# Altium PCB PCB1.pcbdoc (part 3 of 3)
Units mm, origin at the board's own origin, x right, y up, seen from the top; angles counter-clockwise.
Board outline 85.01 x 107.37 mm, 4 copper layers (Top Layer, Inner1, Inner2, Bottom Layer); 103 components, 144 nets, 660 pads, 278 vias.

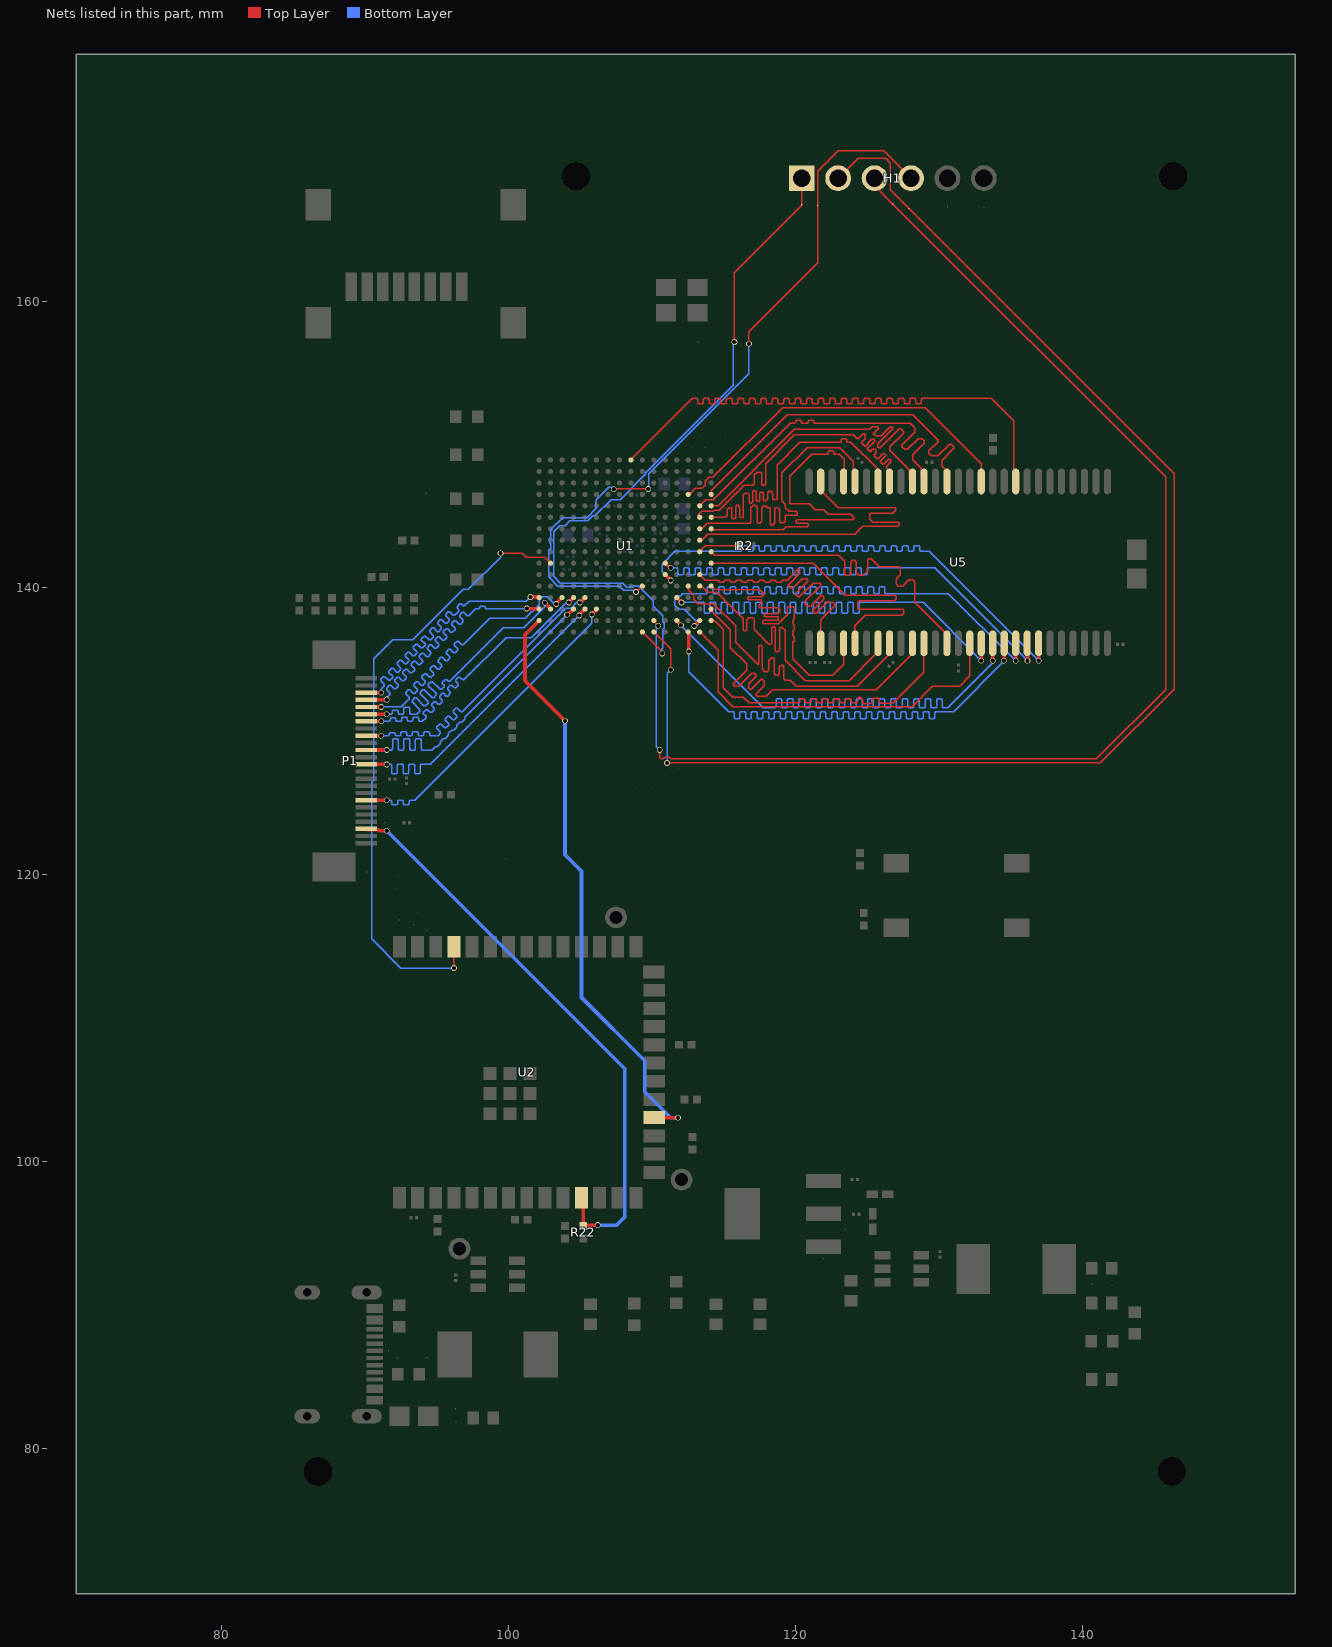
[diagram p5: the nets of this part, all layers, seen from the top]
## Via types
v1: diameter 0.4, hole 0.3, Top Layer to Bottom Layer, 262 vias
v2: diameter 0.61, hole 0.305, Top Layer to Bottom Layer, 16 vias

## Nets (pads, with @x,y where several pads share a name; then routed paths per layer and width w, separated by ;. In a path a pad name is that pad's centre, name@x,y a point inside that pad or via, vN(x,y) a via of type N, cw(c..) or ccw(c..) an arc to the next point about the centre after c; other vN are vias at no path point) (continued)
SD_A12: U1.A9 U5.36 | length 45.3
  Top Layer w0.1: U1.A9@108.528,148.926 112.815,153.213 113.115,153.213 113.186,153.142 113.186,152.903 113.256,152.832 113.515,152.832 113.586,152.903 113.586,153.142 113.656,153.213 113.915,153.213 113.986,153.142 113.986,152.903 114.056,152.832 114.315,152.832 114.386,152.903 114.386,153.142 114.456,153.213 114.715,153.213 114.786,153.142 114.786,152.903 114.856,152.832 115.115,152.832 115.186,152.903 115.186,153.142 115.256,153.213 115.515,153.213 115.586,153.142 115.586,152.903 115.656,152.832 115.915,152.832 115.986,152.903 115.986,153.142 116.056,153.213 116.315,153.213 116.386,153.142 116.386,152.903 116.456,152.832 116.715,152.832 116.786,152.903 116.786,153.142 116.856,153.213 117.115,153.213 117.186,153.142 117.186,152.903 117.256,152.832 117.515,152.832 117.586,152.903 117.586,153.142 117.656,153.213 117.915,153.213 117.986,153.142 117.986,152.903 118.056,152.832 118.315,152.832 118.386,152.903 118.386,153.142 118.456,153.213 118.715,153.213 118.786,153.142 118.786,152.903 118.856,152.832 119.115,152.832 119.186,152.903 119.186,153.142 119.256,153.213 119.515,153.213 119.586,153.142 119.586,152.903 119.656,152.832 119.915,152.832 119.986,152.903 119.986,153.142 120.056,153.213 120.315,153.213 120.386,153.142 120.386,152.903 120.456,152.832 120.715,152.832 120.786,152.903 120.786,153.142 120.856,153.213 121.115,153.213 121.186,153.142 121.186,152.903 121.256,152.832 121.515,152.832 121.586,152.903 121.586,153.142 121.656,153.213 121.915,153.213 121.986,153.142 121.986,152.903 122.056,152.832 122.315,152.832 122.386,152.903 122.386,153.142 122.456,153.213 122.715,153.213 122.786,153.142 122.786,152.903 122.856,152.832 123.115,152.832 123.186,152.903 123.186,153.142 123.256,153.213 123.515,153.213 123.586,153.142 123.586,152.903 123.656,152.832 123.915,152.832 123.986,152.903 123.986,153.142 124.056,153.213 124.315,153.213 124.386,153.142 124.386,152.903 124.456,152.832 124.715,152.832 124.786,152.903 124.786,153.142 124.856,153.213 125.115,153.213 125.186,153.142 125.186,152.903 125.256,152.832 125.515,152.832 125.586,152.903 125.586,153.142 125.656,153.213 125.915,153.213 125.986,153.142 125.986,152.903 126.056,152.832 126.315,152.832 126.386,152.903 126.386,153.142 126.456,153.213 126.715,153.213 126.786,153.142 126.786,152.903 126.856,152.832 127.115,152.832 127.186,152.903 127.186,153.142 127.256,153.213 127.515,153.213 127.586,153.142 127.586,152.903 127.656,152.832 127.915,152.832 127.986,152.903 127.986,153.142 128.056,153.213 128.315,153.213 128.386,153.142 128.386,152.903 128.456,152.832 128.715,152.832 128.786,152.903 128.786,153.142 128.856,153.213 133.655,153.213 135.225,151.643 135.225,147.823 135.242,147.806 135.242,147.552 U5.36@135.369,147.425
SD_BA0: U1.K12 U5.20 | length 43.4
  Top Layer w0.254: U1.K12@110.928,141.726 111.254,141.4 v1(111.301,141.4) ; U5.20@136.169,136.141 136.195,136.115 v1(136.195,134.925)
  Bottom Layer w0.1: v1(111.301,141.4) 111.742,141.4 111.813,141.33 111.813,140.974 111.884,140.903 112.142,140.903 112.213,140.974 112.213,141.33 112.284,141.4 112.542,141.4 112.613,141.33 112.613,140.974 112.684,140.903 112.942,140.903 113.013,140.974 113.013,141.33 113.084,141.4 113.342,141.4 113.413,141.33 113.413,140.974 113.484,140.903 113.742,140.903 113.813,140.974 113.813,141.33 113.884,141.4 114.142,141.4 114.213,141.33 114.213,140.974 114.284,140.903 114.542,140.903 114.613,140.974 114.613,141.33 114.684,141.4 114.942,141.4 115.013,141.33 115.013,140.974 115.084,140.903 115.342,140.903 115.413,140.974 115.413,141.33 115.484,141.4 115.742,141.4 115.813,141.33 115.813,140.974 115.884,140.903 116.142,140.903 116.213,140.974 116.213,141.33 116.284,141.4 116.542,141.4 116.613,141.33 116.613,140.974 116.684,140.903 116.942,140.903 117.013,140.974 117.013,141.33 117.084,141.4 117.342,141.4 117.413,141.33 117.413,140.974 117.484,140.903 117.742,140.903 117.813,140.974 117.813,141.33 117.884,141.4 118.142,141.4 118.213,141.33 118.213,140.974 118.284,140.903 118.542,140.903 118.613,140.974 118.613,141.33 118.684,141.4 118.942,141.4 119.013,141.33 119.013,140.974 119.084,140.903 119.342,140.903 119.413,140.974 119.413,141.33 119.484,141.4 119.742,141.4 119.813,141.33 119.813,140.974 119.884,140.903 120.142,140.903 120.213,140.974 120.213,141.33 120.284,141.4 120.542,141.4 120.613,141.33 120.613,140.974 120.684,140.903 120.942,140.903 121.013,140.974 121.013,141.33 121.084,141.4 121.342,141.4 121.413,141.33 121.413,140.974 121.484,140.903 121.742,140.903 121.813,140.974 121.813,141.33 121.884,141.4 122.142,141.4 122.213,141.33 122.213,140.974 122.284,140.903 122.542,140.903 122.613,140.974 122.613,141.33 122.684,141.4 122.942,141.4 123.013,141.33 123.013,140.974 123.084,140.903 123.342,140.903 123.413,140.974 123.413,141.33 123.484,141.4 123.742,141.4 123.813,141.33 123.813,140.974 123.884,140.903 124.142,140.903 124.213,140.974 124.213,141.33 124.284,141.4 124.542,141.4 124.613,141.33 124.613,140.974 124.684,140.903 124.942,140.903 125.013,140.974 125.013,141.33 125.084,141.4 129.72,141.4 v1(136.195,134.925)
SD_BA1: U1.L12 U5.21 | length 42.5
  Top Layer w0.254: U1.L12@110.928,140.926 111.303,140.551 v1(111.303,140.513) ; v1(136.969,134.925) U5.21@136.969,136.141
  Bottom Layer w0.1: v1(111.303,140.513) 110.699,141.117 110.699,141.65 111.595,142.545 116.202,142.545 116.273,142.616 116.273,142.855 116.344,142.926 116.602,142.926 116.673,142.855 116.673,142.616 116.744,142.545 117.002,142.545 117.073,142.616 117.073,142.855 117.144,142.926 117.402,142.926 117.473,142.855 117.473,142.616 117.544,142.545 117.802,142.545 117.873,142.616 117.873,142.855 117.944,142.926 118.202,142.926 118.273,142.855 118.273,142.616 118.344,142.545 118.602,142.545 118.673,142.616 118.673,142.855 118.744,142.926 119.002,142.926 119.073,142.855 119.073,142.616 119.144,142.545 119.402,142.545 119.473,142.616 119.473,142.855 119.544,142.926 119.802,142.926 119.873,142.855 119.873,142.616 119.944,142.545 120.202,142.545 120.273,142.616 120.273,142.855 120.344,142.926 120.602,142.926 120.673,142.855 120.673,142.616 120.744,142.545 121.002,142.545 121.073,142.616 121.073,142.855 121.144,142.926 121.402,142.926 121.473,142.855 121.473,142.616 121.544,142.545 121.802,142.545 121.873,142.616 121.873,142.855 121.944,142.926 122.202,142.926 122.273,142.855 122.273,142.616 122.344,142.545 122.602,142.545 122.673,142.616 122.673,142.855 122.744,142.926 123.002,142.926 123.073,142.855 123.073,142.616 123.144,142.545 123.402,142.545 123.473,142.616 123.473,142.855 123.544,142.926 123.802,142.926 123.873,142.855 123.873,142.616 123.944,142.545 124.202,142.545 124.273,142.616 124.273,142.855 124.344,142.926 124.602,142.926 124.673,142.855 124.673,142.616 124.744,142.545 125.002,142.545 125.073,142.616 125.073,142.855 125.144,142.926 125.402,142.926 125.473,142.855 125.473,142.616 125.544,142.545 125.802,142.545 125.873,142.616 125.873,142.855 125.944,142.926 126.202,142.926 126.273,142.855 126.273,142.616 126.344,142.545 126.602,142.545 126.673,142.616 126.673,142.855 126.744,142.926 127.002,142.926 127.073,142.855 127.073,142.616 127.144,142.545 127.402,142.545 127.473,142.616 127.473,142.855 127.544,142.926 127.802,142.926 127.873,142.855 127.873,142.616 127.944,142.545 128.202,142.545 128.273,142.616 128.273,142.855 128.344,142.926 128.602,142.926 128.673,142.855 128.673,142.616 128.744,142.545 129.349,142.545 v1(136.969,134.925)
SD_CAS_N: U1.R13 U5.17 | length 43.1
  Top Layer w0.254: U1.R13@111.728,137.726 111.728,137.678 v1(112.017,137.39) ; v1(133.769,134.925) U5.17@133.769,136.141
  Bottom Layer w0.1: v1(112.017,137.39) 117.76,131.646 118.58,131.646 118.651,131.717 118.651,132.187 118.721,132.258 118.98,132.258 119.051,132.187 119.051,131.717 119.121,131.646 119.38,131.646 119.451,131.717 119.451,132.187 119.521,132.258 119.78,132.258 119.851,132.187 119.851,131.717 119.921,131.646 120.18,131.646 120.251,131.717 120.251,132.187 120.321,132.258 120.58,132.258 120.651,132.187 120.651,131.717 120.721,131.646 120.98,131.646 121.051,131.717 121.051,132.187 121.121,132.258 121.38,132.258 121.451,132.187 121.451,131.717 121.521,131.646 121.78,131.646 121.851,131.717 121.851,132.187 121.921,132.258 122.18,132.258 122.251,132.187 122.251,131.717 122.321,131.646 122.58,131.646 122.651,131.717 122.651,132.187 122.721,132.258 122.98,132.258 123.051,132.187 123.051,131.717 123.121,131.646 123.38,131.646 123.451,131.717 123.451,132.187 123.521,132.258 123.78,132.258 123.851,132.187 123.851,131.717 123.921,131.646 124.18,131.646 124.251,131.717 124.251,132.187 124.321,132.258 124.58,132.258 124.651,132.187 124.651,131.717 124.721,131.646 124.98,131.646 125.051,131.717 125.051,132.187 125.121,132.258 125.38,132.258 125.451,132.187 125.451,131.717 125.521,131.646 125.78,131.646 125.851,131.717 125.851,132.187 125.921,132.258 126.18,132.258 126.251,132.187 126.251,131.717 126.321,131.646 126.58,131.646 126.651,131.717 126.651,132.187 126.721,132.258 126.98,132.258 127.051,132.187 127.051,131.717 127.121,131.646 127.38,131.646 127.451,131.717 127.451,132.187 127.521,132.258 127.78,132.258 127.851,132.187 127.851,131.717 127.921,131.646 128.18,131.646 128.251,131.717 128.251,132.187 128.321,132.258 128.58,132.258 128.651,132.187 128.651,131.717 128.721,131.646 128.98,131.646 129.051,131.717 129.051,132.187 129.121,132.258 129.38,132.258 129.451,132.187 129.451,131.717 129.521,131.646 129.78,131.646 129.851,131.717 129.851,132.187 129.921,132.258 130.18,132.258 130.251,132.187 130.251,131.717 130.321,131.646 130.621,131.646 133.769,134.794 v1(133.769,134.925)
SD_CLK: R2.2 U1.J15 | length 2.9
  Top Layer w0.1: U1.J15@113.328,142.526 113.728,142.926 R2.2@116.077,142.926
SD_CS_N: U1.R15 U5.19 | length 43
  Top Layer w0.254: v1(112.954,137.338) 113.328,137.712 U1.R15@113.328,137.726 ; v1(135.369,134.925) U5.19@135.369,136.141
  Bottom Layer w0.1: v1(112.954,137.338) 113.081,137.338 113.25,137.507 112.248,138.51 111.867,138.51 111.586,138.791 111.586,139.187 111.867,139.468 111.994,139.468 112.121,139.595 113.781,139.595 113.851,139.666 113.851,139.995 113.922,140.066 114.181,140.066 114.251,139.995 114.251,139.666 114.322,139.595 114.581,139.595 114.651,139.666 114.651,139.995 114.722,140.066 114.981,140.066 115.051,139.995 115.051,139.666 115.122,139.595 115.381,139.595 115.451,139.666 115.451,139.995 115.522,140.066 115.781,140.066 115.851,139.995 115.851,139.666 115.922,139.595 116.181,139.595 116.251,139.666 116.251,139.995 116.322,140.066 116.581,140.066 116.651,139.995 116.651,139.666 116.722,139.595 116.981,139.595 117.051,139.666 117.051,139.995 117.122,140.066 117.381,140.066 117.451,139.995 117.451,139.666 117.522,139.595 117.781,139.595 117.851,139.666 117.851,139.995 117.922,140.066 118.181,140.066 118.251,139.995 118.251,139.666 118.322,139.595 118.581,139.595 118.651,139.666 118.651,139.995 118.722,140.066 118.981,140.066 119.051,139.995 119.051,139.666 119.122,139.595 119.381,139.595 119.451,139.666 119.451,139.995 119.522,140.066 119.781,140.066 119.851,139.995 119.851,139.666 119.922,139.595 120.181,139.595 120.251,139.666 120.251,139.995 120.322,140.066 120.581,140.066 120.651,139.995 120.651,139.666 120.722,139.595 120.981,139.595 121.051,139.666 121.051,139.995 121.122,140.066 121.381,140.066 121.451,139.995 121.451,139.666 121.522,139.595 121.781,139.595 121.851,139.666 121.851,139.995 121.922,140.066 122.181,140.066 122.251,139.995 122.251,139.666 122.322,139.595 122.581,139.595 122.651,139.666 122.651,139.995 122.722,140.066 122.981,140.066 123.051,139.995 123.051,139.666 123.122,139.595 123.381,139.595 123.451,139.666 123.451,139.995 123.522,140.066 123.781,140.066 123.851,139.995 123.851,139.666 123.922,139.595 124.181,139.595 124.251,139.666 124.251,139.995 124.322,140.066 124.581,140.066 124.651,139.995 124.651,139.666 124.722,139.595 124.981,139.595 125.051,139.666 125.051,139.995 125.122,140.066 125.381,140.066 125.451,139.995 125.451,139.666 125.522,139.595 125.781,139.595 125.851,139.666 125.851,139.995 125.922,140.066 126.181,140.066 126.251,139.995 126.251,139.666 126.322,139.595 130.678,139.595 135.221,135.052 135.242,135.052 v1(135.369,134.925)
SD_DQ0: U1.L15 U5.2 | length 25
  Top Layer w0.1: U1.L15@113.328,140.926 113.71,140.544 114.577,140.544 114.648,140.473 114.648,140.457 114.718,140.386 114.977,140.386 115.048,140.457 115.048,140.473 115.118,140.544 115.377,140.544 115.448,140.473 115.448,140.457 115.518,140.386 115.777,140.386 115.848,140.457 115.848,140.473 115.918,140.544 116.177,140.544 116.248,140.473 116.248,140.457 116.318,140.386 116.577,140.386 116.648,140.457 116.648,140.473 116.718,140.544 116.977,140.544 117.048,140.473 117.048,140.457 117.118,140.386 117.377,140.386 117.448,140.457 117.448,140.473 117.518,140.544 117.777,140.544 117.848,140.473 117.848,140.457 117.918,140.386 118.177,140.386 118.248,140.457 118.248,140.473 118.318,140.544 118.577,140.544 118.648,140.473 118.648,140.457 118.718,140.386 118.977,140.386 119.048,140.457 119.048,140.473 119.118,140.544 119.418,140.544 120.179,141.304 120.291,141.304 120.32,141.275 120.32,141.021 119.497,140.198 119.497,140.066 119.558,140.005 119.859,140.005 120.494,140.64 120.803,140.64 120.874,140.569 120.874,140.469 120.066,139.661 120.066,139.497 120.193,139.37 120.284,139.37 121.243,140.33 121.698,140.33 121.769,140.259 121.769,140.165 120.701,139.097 120.701,138.862 120.828,138.735 121.082,138.735 121.788,139.441 121.9,139.441 121.971,139.37 121.971,139.218 121.209,138.456 121.209,138.354 121.336,138.227 121.463,138.227 122.225,138.989 122.623,138.989 122.743,138.868 122.743,138.768 121.769,137.794 U5.2@121.769,136.268
SD_DQ1: U1.M16 U5.4 | length 25
  Top Layer w0.1: U1.M16@114.128,140.126 114.344,139.91 114.605,139.91 114.643,139.872 117.532,139.872 117.833,139.571 117.662,139.399 116.764,139.399 116.693,139.328 116.693,139.228 116.764,139.158 117.611,139.158 117.653,139.116 117.653,138.977 117.455,138.78 117.455,138.68 117.526,138.609 118.795,138.609 118.902,138.502 118.902,138.333 118.775,138.206 117.907,138.206 117.842,138.141 117.842,138.049 117.907,137.985 118.795,137.985 118.795,137.751 118.778,137.733 117.78,137.733 117.709,137.663 117.709,137.563 117.78,137.492 118.795,137.492 119.431,138.128 119.431,138.608 119.502,138.679 119.868,138.679 119.939,138.608 119.939,137.846 119.812,137.719 119.812,137.515 119.932,137.395 119.932,137.115 119.812,136.995 119.812,136.715 119.932,136.595 119.932,136.315 119.812,136.195 119.812,135.052 120.955,133.909 122.606,133.909 123.369,134.672 U5.4@123.369,136.268
SD_DQ2: U1.K16 U5.5 | length 25.6
  Top Layer w0.1: U1.K16@114.128,141.726 121.266,141.726 123.495,139.497 126.924,139.497 127.051,139.37 127.051,139.243 126.908,139.1 124.476,139.1 124.366,138.989 124.366,138.585 124.426,138.525 127.488,138.525 127.559,138.454 127.559,138.227 127.433,138.101 124.893,138.101 124.152,137.36 124.152,136.539 124.169,136.522 U5.5@124.169,136.268
SD_DQ3: U1.M15 U5.7 | length 24.8
  Top Layer w0.1: U1.M15@113.328,140.126 113.408,140.126 113.422,140.111 113.47,140.111 113.873,139.708 114.521,139.708 116.368,137.861 116.368,137.084 116.438,137.013 116.538,137.013 116.609,137.084 116.609,137.761 116.764,137.916 117.018,137.916 117.118,137.816 117.118,137.111 118.161,136.068 118.288,136.068 118.346,136.126 118.346,137.211 118.417,137.282 118.517,137.282 118.587,137.211 118.587,135.642 118.669,135.56 118.796,135.56 118.92,135.684 118.92,137.211 118.979,137.27 119.062,137.27 119.284,137.048 119.284,134.945 120.701,133.528 123.754,133.528 125.625,135.399 125.625,135.997 125.642,136.014 125.642,136.141 U5.7@125.769,136.268
SD_DQ4: U1.M14 U5.8 | length 25.8
  Top Layer w0.1: U1.M14@112.528,140.126 112.528,139.866 112.91,139.484 112.91,139.204 113.206,138.908 114.286,138.908 115.848,137.346 115.848,136.195 117.406,134.637 117.438,134.669 117.438,135.941 117.509,136.012 117.609,136.012 117.679,135.941 117.679,134.364 117.88,134.163 118.034,134.163 118.153,134.282 118.153,134.904 118.371,135.123 118.471,135.123 118.542,135.052 118.542,134.009 118.642,133.909 118.796,133.909 118.888,134.001 118.888,134.497 119.006,134.615 119.106,134.615 119.177,134.544 119.177,133.677 119.304,133.55 119.644,133.55 120.047,133.147 124.318,133.147 126.726,135.555 126.726,136.111 U5.8@126.569,136.268
SD_DQ5: U1.P16 U5.10 | length 25.6
  Top Layer w0.1: U1.P16@114.128,138.526 114.128,138.417 115.473,137.072 115.473,135.835 116.607,134.701 116.607,134.247 115.677,133.318 115.677,133.218 115.748,133.147 116.068,133.147 116.957,134.036 117.145,134.036 117.272,133.909 117.272,133.843 116.751,133.323 116.751,133.007 116.822,132.937 116.922,132.937 117.647,133.661 117.816,133.492 117.816,133.17 117.265,132.619 117.265,132.519 117.336,132.448 117.97,132.448 118.415,132.893 125.646,132.893 128.169,135.416 U5.10@128.169,136.268
SD_DQ6: U1.R16 U5.11 | length 25.2
  Top Layer w0.1: U1.R16@114.128,137.726 114.392,137.726 114.986,137.132 114.986,133.02 115.617,132.389 116.379,132.389 116.78,131.988 120.222,131.988 120.292,132.059 120.292,132.187 120.363,132.258 120.622,132.258 120.692,132.187 120.692,132.059 120.763,131.988 121.022,131.988 121.092,132.059 121.092,132.187 121.163,132.258 121.422,132.258 121.492,132.187 121.492,132.059 121.563,131.988 121.822,131.988 121.892,132.059 121.892,132.187 121.963,132.258 122.222,132.258 122.292,132.187 122.292,132.059 122.363,131.988 122.622,131.988 122.692,132.059 122.692,132.187 122.763,132.258 123.022,132.258 123.092,132.187 123.092,132.059 123.163,131.988 123.422,131.988 123.492,132.059 123.492,132.187 123.563,132.258 123.822,132.258 123.892,132.187 123.892,132.059 123.963,131.988 124.24,131.988 124.34,132.088 124.34,132.314 124.411,132.385 124.511,132.385 124.717,132.179 124.717,131.928 125.229,131.928 125.329,132.028 125.329,132.187 125.456,132.314 125.781,132.314 125.852,132.244 125.852,132.058 125.952,131.958 126.783,131.958 128.956,134.131 U5.11@128.956,135.763
SD_DQ7: U1.J16 U5.13 | length 25.2
  Top Layer w0.1: U1.J16@114.128,142.526 114.363,142.291 123.015,142.291 123.451,141.854 123.451,140.952 123.522,140.881 123.763,140.881 123.863,140.981 123.863,141.783 124,141.919 124.121,141.919 124.259,141.781 124.259,141.046 124.424,140.881 124.752,140.881 125.035,141.164 125.035,141.926 125.146,142.037 125.289,142.037 125.857,141.469 125.861,141.473 127.234,141.473 127.305,141.402 127.305,140.903 127.051,140.649 127.051,140.275 127.194,140.132 127.491,140.132 127.926,140.568 128.194,140.568 128.323,140.438 128.323,139.004 ; 128.323,139.003 130.569,136.757 U5.13@130.569,136.268
SD_DQ8: U1.D16 U5.42 | length 25.2
  Top Layer w0.1: U1.D16@114.128,146.526 114.128,146.78 119.418,152.07 128.194,152.07 129.972,150.292 129.972,150.211 129.316,149.555 129.316,149.403 129.504,149.215 129.938,149.215 130.761,150.038 130.861,150.038 131.059,149.84 131.059,149.728 130.988,149.657 130.982,149.657 130.205,148.88 130.205,148.514 130.442,148.277 130.442,147.679 U5.42@130.569,147.552
SD_DQ9: U1.E15 U5.44 | length 25
  Top Layer w0.1: U1.E15@113.328,145.726 113.746,146.144 114.286,146.144 119.641,151.499 119.941,151.499 120.011,151.569 120.011,151.618 120.082,151.689 120.341,151.689 120.411,151.618 120.411,151.569 120.482,151.499 120.827,151.499 120.898,151.569 120.898,151.618 120.969,151.689 121.227,151.689 121.298,151.618 121.298,151.569 121.369,151.499 128.004,151.499 128.321,151.181 128.321,150.842 127.432,149.953 127.432,149.845 127.62,149.657 127.813,149.657 128.575,150.419 128.829,150.419 128.998,150.25 128.998,150.108 128.194,149.304 128.194,148.925 128.778,148.341 128.778,147.743 U5.44@128.969,147.552
SD_DQ10: U1.E16 U5.45 | length 25
  Top Layer w0.1: U1.E16@114.128,145.726 114.611,145.726 119.939,151.054 125.156,151.054 125.354,151.252 125.71,151.252 125.781,151.181 125.781,151.095 125.448,150.762 125.606,150.604 125.979,150.604 126.626,151.252 126.726,151.252 126.797,151.181 126.797,151.114 125.751,150.068 125.751,149.841 125.822,149.771 125.922,149.771 127.255,151.104 127.355,151.104 127.559,150.9 127.559,150.8 126.598,149.839 126.598,149.612 127.821,148.389 127.821,148.384 127.955,148.25 127.955,147.652 128.055,147.552 U5.45@128.169,147.552
SD_DQ11: U1.F15 U5.47 | length 25.1
  Top Layer w0.1: U1.F15@113.328,144.926 113.201,145.053 113.201,145.078 113.467,145.344 114.286,145.344 114.377,145.435 114.701,145.435 116.439,147.173 117.074,147.173 117.145,147.244 117.145,147.879 117.348,148.082 117.553,148.082 117.653,147.982 117.653,147.244 117.724,147.173 117.873,147.173 117.944,147.244 117.944,148.678 119.939,150.673 124.046,150.673 124.306,150.413 124.391,150.413 124.721,150.744 124.821,150.744 124.892,150.673 124.892,150.419 124.638,150.165 124.638,150.081 124.824,149.896 124.877,149.896 125.344,150.363 125.456,150.363 125.527,150.292 125.527,150.247 125.019,149.739 125.019,149.7 125.219,149.501 125.375,149.657 125.591,149.657 125.654,149.594 125.654,149.434 125.496,149.276 125.496,149.223 125.697,149.022 125.781,149.022 126.106,149.347 126.218,149.347 126.289,149.276 126.289,149.227 125.908,148.846 125.908,148.811 126.103,148.616 126.15,148.616 126.499,148.966 126.599,148.966 126.67,148.895 126.67,148.797 126.332,148.459 126.332,148.387 126.569,148.15 U5.47@126.569,147.552
SD_DQ12: U1.F16 U5.48 | length 25.1
  Top Layer w0.1: U1.F16@114.128,144.926 115.081,144.926 115.24,145.085 115.24,145.466 115.367,145.593 115.534,145.593 115.577,145.549 115.577,144.902 115.648,144.831 115.748,144.831 115.856,144.939 115.856,145.701 115.914,145.759 116.002,145.759 116.137,145.624 116.137,144.962 116.212,144.887 116.312,144.887 116.383,144.958 116.383,146.482 116.51,146.609 116.696,146.609 116.777,146.529 116.777,145.974 116.847,145.903 116.916,145.903 117.018,146.006 117.018,146.731 117.081,146.794 117.214,146.794 117.285,146.723 117.285,146.101 117.355,146.03 117.455,146.03 117.526,146.101 117.526,146.609 117.59,146.673 117.716,146.673 117.751,146.638 117.751,146.157 117.822,146.086 117.922,146.086 118.063,146.228 118.063,146.638 118.161,146.736 118.288,146.736 118.415,146.609 118.415,146.228 118.486,146.157 118.654,146.157 118.725,146.228 118.725,148.57 120.32,150.165 123.129,150.165 123.199,150.236 123.199,150.348 123.27,150.419 123.529,150.419 123.599,150.348 123.599,150.236 123.67,150.165 123.876,150.165 125.711,148.33 125.711,147.652 125.769,147.594 U5.48@125.769,147.552
SD_DQ13: U1.G15 U5.50 | length 25.1
  Top Layer w0.1: U1.G15@113.328,144.126 113.469,144.126 113.851,144.508 116.822,144.508 116.891,144.577 116.891,145.593 117.074,145.776 117.216,145.776 117.343,145.649 117.343,144.577 117.413,144.506 117.513,144.506 117.653,144.646 117.653,145.593 117.78,145.72 117.907,145.72 118.034,145.593 118.25,145.593 118.25,144.45 118.321,144.379 118.421,144.379 118.58,144.539 118.58,145.536 118.637,145.593 118.796,145.593 118.923,145.466 118.923,144.65 119.023,144.55 119.204,144.55 119.304,144.65 119.304,145.043 119.346,145.085 120.066,145.085 120.137,145.156 120.137,145.256 120.058,145.334 119.563,145.334 119.304,145.593 119.304,145.834 119.062,146.077 119.062,148.024 120.822,149.784 123.114,149.784 124.051,148.847 124.051,147.671 U5.50@124.169,147.552
SD_DQ14: U1.G16 U5.51 | length 25
  Top Layer w0.1: U1.G16@114.128,144.126 114.191,144.062 119.17,144.062 119.364,144.256 120.828,144.256 120.899,144.327 120.899,144.427 120.828,144.497 120.146,144.497 120.033,144.61 120.033,144.671 120.128,144.766 124.003,144.766 124.074,144.836 124.074,144.936 123.854,145.156 122.308,145.156 121.998,145.466 121.374,145.466 120.955,145.885 119.605,145.885 119.605,147.799 121.146,149.34 122.209,149.34 122.28,149.41 122.28,149.484 122.35,149.555 122.609,149.555 122.68,149.484 122.68,149.41 122.751,149.34 123.051,149.34 123.415,148.975 123.415,147.887 U5.51@123.433,147.87
SD_DQ15: U1.H15 U5.53 | length 25.3
  Top Layer w0.1: U1.H15@113.328,143.326 113.455,143.326 113.873,143.744 124.159,143.744 124.716,144.301 127.144,144.301 127.249,144.406 127.249,144.506 127.178,144.577 125.4,144.577 125.202,144.775 125.202,145.141 125.273,145.212 126.784,145.212 126.995,145.422 126.995,145.522 126.924,145.593 122.987,145.593 121.896,146.684 U5.53@121.896,147.425
SD_DQM0: U1.T15 U5.15 | length 25.8
  Top Layer w0.1: U1.T15@113.328,136.926 114.605,135.649 114.605,132.766 115.643,131.728 128.138,131.728 129.558,133.147 131.456,133.147 132.169,133.86 U5.15@132.169,136.141
SD_DQM1: U1.D14 U5.39 | length 25.9
  Top Layer w0.1: U1.D14@112.528,146.526 112.617,146.526 113.035,146.944 113.486,146.944 113.71,147.168 113.71,147.448 113.97,147.708 114.25,147.708 119.12,152.578 129.067,152.578 132.978,148.668 132.978,147.679 U5.39@132.851,147.552
SD_RAS_N: U1.T14 U5.18 | length 43.8
  Top Layer w0.254: v1(112.573,135.56) U1.T14@112.573,136.76 ; v1(134.544,134.925) 134.569,134.95 U5.18@134.569,136.141
  Bottom Layer w0.1: v1(112.573,135.56) 112.573,134.163 115.367,131.369 115.667,131.369 115.738,131.298 115.738,130.932 115.808,130.861 116.067,130.861 116.138,130.932 116.138,131.298 116.208,131.369 116.467,131.369 116.538,131.298 116.538,130.932 116.608,130.861 116.867,130.861 116.938,130.932 116.938,131.298 117.008,131.369 117.267,131.369 117.338,131.298 117.338,130.932 117.408,130.861 117.667,130.861 117.738,130.932 117.738,131.298 117.808,131.369 118.067,131.369 118.138,131.298 118.138,130.932 118.208,130.861 118.467,130.861 118.538,130.932 118.538,131.298 118.608,131.369 118.867,131.369 118.938,131.298 118.938,130.932 119.008,130.861 119.267,130.861 119.338,130.932 119.338,131.298 119.408,131.369 119.667,131.369 119.738,131.298 119.738,130.932 119.808,130.861 120.067,130.861 120.138,130.932 120.138,131.298 120.208,131.369 120.467,131.369 120.538,131.298 120.538,130.932 120.608,130.861 120.867,130.861 120.938,130.932 120.938,131.298 121.008,131.369 121.267,131.369 121.338,131.298 121.338,130.932 121.408,130.861 121.667,130.861 121.738,130.932 121.738,131.298 121.808,131.369 122.067,131.369 122.138,131.298 122.138,130.932 122.208,130.861 122.467,130.861 122.538,130.932 122.538,131.298 122.608,131.369 122.867,131.369 122.938,131.298 122.938,130.932 123.008,130.861 123.267,130.861 123.338,130.932 123.338,131.298 123.408,131.369 123.667,131.369 123.738,131.298 123.738,130.932 123.808,130.861 124.067,130.861 124.138,130.932 124.138,131.298 124.208,131.369 124.467,131.369 124.538,131.298 124.538,130.932 124.608,130.861 124.867,130.861 124.938,130.932 124.938,131.298 125.008,131.369 125.267,131.369 125.338,131.298 125.338,130.932 125.408,130.861 125.667,130.861 125.738,130.932 125.738,131.298 125.808,131.369 126.067,131.369 126.138,131.298 126.138,130.932 126.208,130.861 126.467,130.861 126.538,130.932 126.538,131.298 126.608,131.369 126.867,131.369 126.938,131.298 126.938,130.932 127.008,130.861 127.267,130.861 127.338,130.932 127.338,131.298 127.408,131.369 127.667,131.369 127.738,131.298 127.738,130.932 127.808,130.861 128.067,130.861 128.138,130.932 128.138,131.298 128.208,131.369 128.467,131.369 128.538,131.298 128.538,130.932 128.608,130.861 128.867,130.861 128.938,130.932 128.938,131.298 129.008,131.369 129.267,131.369 129.338,131.298 129.338,130.932 129.408,130.861 129.667,130.861 129.738,130.932 129.738,131.298 129.808,131.369 131.036,131.369 134.544,134.877 v1(134.544,134.925)
SD_WE_N: U1.N13 U5.16 | length 43.3
  Top Layer w0.254: U1.N13@111.728,139.326 v1(112.065,138.989) ; v1(132.969,134.925) U5.16@132.969,136.141
  Bottom Layer w0.1: v1(112.065,138.989) 113.573,138.989 113.644,138.918 113.644,138.298 113.715,138.227 113.973,138.227 114.044,138.298 114.044,138.918 114.115,138.989 114.373,138.989 114.444,138.918 114.444,138.298 114.515,138.227 114.773,138.227 114.844,138.298 114.844,138.918 114.915,138.989 115.173,138.989 115.244,138.918 115.244,138.298 115.315,138.227 115.573,138.227 115.644,138.298 115.644,138.918 115.715,138.989 115.973,138.989 116.044,138.918 116.044,138.298 116.115,138.227 116.373,138.227 116.444,138.298 116.444,138.918 116.515,138.989 116.773,138.989 116.844,138.918 116.844,138.298 116.915,138.227 117.173,138.227 117.244,138.298 117.244,138.918 117.315,138.989 117.573,138.989 117.644,138.918 117.644,138.298 117.715,138.227 117.973,138.227 118.044,138.298 118.044,138.918 118.115,138.989 118.373,138.989 118.444,138.918 118.444,138.298 118.515,138.227 118.773,138.227 118.844,138.298 118.844,138.918 118.915,138.989 119.173,138.989 119.244,138.918 119.244,138.298 119.315,138.227 119.573,138.227 119.644,138.298 119.644,138.918 119.715,138.989 119.973,138.989 120.044,138.918 120.044,138.298 120.115,138.227 120.373,138.227 120.444,138.298 120.444,138.918 120.515,138.989 120.773,138.989 120.844,138.918 120.844,138.298 120.915,138.227 121.173,138.227 121.244,138.298 121.244,138.918 121.315,138.989 121.573,138.989 121.644,138.918 121.644,138.298 121.715,138.227 121.973,138.227 122.044,138.298 122.044,138.918 122.115,138.989 122.373,138.989 122.444,138.918 122.444,138.298 122.515,138.227 122.773,138.227 122.844,138.298 122.844,138.918 122.915,138.989 123.173,138.989 123.244,138.918 123.244,138.298 123.315,138.227 123.573,138.227 123.644,138.298 123.644,138.918 123.715,138.989 123.973,138.989 124.044,138.918 124.044,138.298 124.115,138.227 124.373,138.227 124.444,138.298 124.444,138.918 124.515,138.989 128.905,138.989 v1(132.969,134.925)
SDA: P1.3 R22.1 U2.11 | length 40.4
  Top Layer w0.254: P1.3@90.08,123.194 90.151,123.124 90.945,123.124 91.001,123.067 v1(91.491,123.067) ; R22.1@105.202,95.555 U2.11@105.202,97.473 ; R22.1@105.207,95.48 105.282,95.555 v1(106.223,95.555)
  Bottom Layer w0.254: v1(91.491,123.067) 108.099,106.459 108.099,96.119 107.535,95.555 v1(106.223,95.555)
SSPI_CS_N: U1.R1 U2.18 | length 41.3
  Top Layer w0.254: U1.R1@102.128,137.726 101.143,136.741 101.143,133.528 v1(103.937,130.734) ; U2.18@110.292,103.048 v1(111.811,103.048)
  Bottom Layer w0.254: v1(103.937,130.734) 103.937,121.38 105.08,120.237 105.08,111.43 109.498,107.012 109.498,104.853 111.303,103.048 v1(111.811,103.048)
TCK: H1.1 pad.55@120.444,166.728 U1.T10 | length 50.3
  Top Layer w0.1: U1.T10@109.328,136.926 110.712,135.542 v1(110.712,135.433) ; v1(115.748,157.15) 115.748,161.976 120.447,166.675 H1.1@120.447,168.58
  Bottom Layer w0.1: v1(110.712,135.433) 110.618,135.527 110.618,135.669 110.738,135.789 110.738,136.858 110.749,136.869 110.749,137.104 110.843,137.199 110.843,137.532 110.749,137.626 110.749,138.049 110.075,138.723 110.075,139.1 109.032,140.143 108.748,140.143 108.648,140.043 108.242,140.043 107.953,140.332 103.61,140.332 103.142,140.8 103.142,143.909 103.573,144.34 103.946,144.34 104.274,144.668 105.523,144.668 105.878,145.023 106.002,145.023 107.145,146.166 107.79,146.166 109.579,147.955 109.579,148.049 115.654,154.124 115.654,157.056 v1(115.748,157.15)
TDI: H1.3 pad.55@126.796,166.776 U1.R11 | length 91.4
  Top Layer w0.1: U1.R11@110.128,137.726 110.128,137.678 v1(110.441,137.365) ; v1(110.541,128.702) 110.541,128.167 110.641,128.067 110.755,128.067 110.882,128.194 111.216,128.194 111.343,128.067 140.994,128.067 145.82,132.893 145.82,147.752 pad.55@126.796,166.776 125.527,168.045 H1.3@125.527,168.58
  Bottom Layer w0.1: v1(110.441,137.365) 110.31,137.234 110.31,128.933 v1(110.541,128.702)
TDO: H1.4 pad.55@121.549,166.687 U1.M10 | length 53.9
  Top Layer w0.1: v1(107.328,146.878) 107.358,146.908 109.734,146.908 v1(109.746,146.896) ; v1(108.89,139.716) 108.918,139.716 U1.M10@109.328,140.126 ; v1(116.764,157.023) 116.764,157.883 121.549,162.668 pad.55@121.549,166.687 121.549,169.047 122.987,170.485 126.162,170.485 H1.4@128.067,168.58
  Bottom Layer w0.1: v1(107.328,146.878) 107.201,147.005 106.972,147.005 106.117,146.151 106.117,145.994 106.09,145.967 106.09,145.526 105.474,144.911 103.763,144.911 102.93,144.078 102.93,143.521 102.881,143.472 102.881,143.154 102.942,143.093 102.942,142.759 102.794,142.611 102.794,140.767 103.429,140.132 107.728,140.132 108.016,139.843 108.763,139.843 v1(108.89,139.716) ; v1@109.779,146.896 109.779,147.966 116.764,154.951 v1(116.764,157.023)
TMS: H1.2 pad.55@127.919,166.471 U1.T11 | length 96.5
  Top Layer w0.1: U1.T11@110.128,136.926 111.303,135.751 v1(111.303,134.29) ; v1(111.049,127.792) 141.283,127.792 146.428,132.937 146.428,147.962 pad.55@127.919,166.471 126.629,167.761 126.629,169.637 126.289,169.977 124.384,169.977 H1.2@122.987,168.58
  Bottom Layer w0.1: v1(111.049,127.792) 111.049,134.036 v1(111.303,134.29)
TX: U1.K2 U2.37 | length 43.6
  Top Layer w0.1: v1@96.185,113.462 U2.37@96.185,114.973 ; v1@99.365,142.418 100.955,142.418 101.23,142.143 102.509,142.143 ; 102.51,142.144 U1.K2@102.928,141.726
  Bottom Layer w0.1: v1(96.185,113.483) 92.486,113.483 90.452,115.517 90.452,126.446 90.602,126.596 90.602,135.052 91.926,136.376 93.298,136.376 96.833,139.911 97.201,139.911 99.44,142.15 v1(99.44,142.418)
VSYNC: P1.7 U1.P6 | length 22.8
  Top Layer w0.254: P1.7@90.08,125.194 v1(91.491,125.194) ; v1(105.796,138.146) 106.128,138.478 U1.P6@106.128,138.526
  Bottom Layer w0.1: v1(91.491,125.194) 91.788,125.194 91.859,125.124 91.859,124.963 91.929,124.892 92.188,124.892 92.259,124.963 92.259,125.124 92.329,125.194 92.588,125.194 92.659,125.124 92.659,124.963 92.729,124.892 92.988,124.892 93.059,124.963 93.059,125.124 93.129,125.194 93.444,125.194 105.796,137.546 v1(105.796,138.146)
Y2: P1.19 U1.P2 | length 23
  Top Layer w0.254: P1.19@90.08,131.194 v1(91.491,131.194) ; v1(102.525,138.971) 102.928,138.567 U1.P2@102.928,138.526
  Bottom Layer w0.1: v1(91.491,131.194) 91.825,131.194 91.896,131.264 91.896,131.396 91.967,131.466 92.225,131.466 92.296,131.396 92.296,131.264 92.367,131.194 92.625,131.194 92.696,131.264 92.696,131.604 92.767,131.675 93.025,131.675 93.096,131.604 93.096,131.264 93.167,131.194 93.602,131.194 93.814,131.406 93.814,131.506 93.276,132.043 93.276,132.143 93.459,132.326 93.559,132.326 94.097,131.789 94.197,131.789 94.379,131.971 94.379,132.071 93.842,132.609 93.842,132.709 94.025,132.892 94.125,132.892 94.662,132.354 94.762,132.354 94.945,132.537 94.945,132.637 94.408,133.174 94.408,133.274 94.591,133.457 94.691,133.457 95.228,132.92 95.328,132.92 95.511,133.103 95.511,133.203 95.386,133.327 95.386,133.427 95.569,133.61 95.669,133.61 95.794,133.486 95.894,133.486 99.631,137.223 101.07,137.223 102.525,138.677 v1(102.525,138.971)
Y3: P1.21 U1.P1 | length 23
  Top Layer w0.254: P1.21@90.083,132.196 90.096,132.209 v1(91.504,132.209) ; v1(101.27,138.558) 102.096,138.558 U1.P1@102.128,138.526
  Bottom Layer w0.1: v1(91.504,132.209) 91.504,132.336 91.738,132.57 91.738,132.67 91.497,132.912 91.497,133.012 91.68,133.194 91.78,133.194 92.021,132.953 92.121,132.953 92.304,133.136 92.304,133.236 92.063,133.477 92.063,133.577 92.246,133.76 92.346,133.76 92.587,133.519 92.687,133.519 92.87,133.702 92.87,133.802 92.628,134.043 92.628,134.143 92.811,134.326 92.911,134.326 93.152,134.085 93.252,134.085 93.435,134.267 93.435,134.367 93.194,134.609 93.194,134.709 93.377,134.892 93.477,134.892 93.718,134.65 93.818,134.65 94.001,134.833 94.001,134.933 93.76,135.174 93.76,135.274 93.943,135.457 94.043,135.457 94.284,135.216 94.384,135.216 94.567,135.399 94.567,135.499 94.325,135.74 94.325,135.84 94.508,136.023 94.608,136.023 94.85,135.782 94.95,135.782 95.132,135.965 95.132,136.065 94.891,136.306 94.891,136.406 95.074,136.589 95.174,136.589 95.415,136.347 95.515,136.347 95.698,136.53 95.698,136.63 95.457,136.871 95.457,136.971 95.64,137.154 95.74,137.154 95.981,136.913 96.081,136.913 96.264,137.096 96.264,137.196 96.023,137.437 96.023,137.537 96.205,137.72 96.305,137.72 96.547,137.479 96.647,137.479 96.829,137.662 96.829,137.762 96.588,138.003 96.588,138.103 96.771,138.286 96.871,138.286 97.112,138.044 97.212,138.044 97.701,138.533 97.914,138.533 97.985,138.604 97.985,138.664 98.056,138.735 98.314,138.735 98.385,138.664 98.385,138.604 98.456,138.533 101.245,138.533 v1(101.27,138.558)
Y4: P1.22 U1.N1 | length 22.9
  Top Layer w0.254: P1.22@90.083,132.696 v1(91.11,132.696) ; v1(101.524,139.37) 102.084,139.37 U1.N1@102.128,139.326
  Bottom Layer w0.1: v1(91.11,132.696) 91.11,132.95 91.341,133.181 91.341,133.281 91.089,133.534 91.089,133.634 91.272,133.817 91.372,133.817 91.624,133.564 91.724,133.564 91.907,133.747 91.907,133.847 91.655,134.1 91.655,134.2 91.837,134.382 91.937,134.382 92.19,134.13 92.29,134.13 92.473,134.313 92.473,134.413 92.22,134.665 92.22,134.765 92.403,134.948 92.503,134.948 92.755,134.696 92.855,134.696 93.038,134.879 93.038,134.979 92.786,135.231 92.786,135.331 92.969,135.514 93.069,135.514 93.321,135.261 93.421,135.261 93.604,135.444 93.604,135.544 93.352,135.797 93.352,135.897 93.534,136.079 93.634,136.079 93.887,135.827 93.987,135.827 94.17,136.01 94.17,136.11 93.917,136.362 93.917,136.462 94.1,136.645 94.2,136.645 94.453,136.393 94.553,136.393 94.735,136.576 94.735,136.676 94.483,136.928 94.483,137.028 94.666,137.211 94.766,137.211 95.018,136.958 95.118,136.958 95.301,137.141 95.301,137.241 95.049,137.494 95.049,137.594 95.232,137.777 95.332,137.777 95.584,137.524 95.684,137.524 95.867,137.707 95.867,137.807 95.614,138.059 95.614,138.159 95.797,138.342 95.897,138.342 96.15,138.09 96.25,138.09 96.537,138.377 96.537,138.477 96.411,138.602 96.411,138.702 96.594,138.885 96.694,138.885 96.819,138.76 96.919,138.76 97.247,139.087 101.241,139.087 v1(101.524,139.37)
Y5: P1.20 U1.N3 | length 23
  Top Layer w0.254: P1.20@90.083,131.696 v1(91.11,131.696) ; v1(103.323,138.883) 103.323,138.921 U1.N3@103.728,139.326
  Bottom Layer w0.1: v1(91.11,131.696) 92.505,131.696 93.067,132.258 93.067,132.358 92.824,132.602 92.824,132.702 93.006,132.884 93.106,132.884 93.35,132.641 93.45,132.641 93.633,132.824 93.633,132.924 93.389,133.167 93.389,133.267 93.572,133.45 93.672,133.45 93.916,133.207 94.016,133.207 94.199,133.39 94.199,133.49 93.955,133.733 93.955,133.833 94.138,134.016 94.238,134.016 94.481,133.772 94.581,133.772 94.764,133.955 94.764,134.055 94.521,134.299 94.521,134.399 94.704,134.582 94.804,134.582 95.047,134.338 95.147,134.338 95.33,134.521 95.33,134.621 95.086,134.864 95.086,134.964 95.269,135.147 95.369,135.147 95.613,134.904 95.713,134.904 95.896,135.087 95.896,135.187 95.652,135.43 95.652,135.53 95.835,135.713 95.935,135.713 96.178,135.469 96.278,135.469 96.461,135.652 96.461,135.752 96.218,135.996 96.218,136.096 96.401,136.279 96.501,136.279 96.744,136.035 96.844,136.035 98.677,137.868 101.148,137.868 102.123,138.842 102.123,139.137 102.358,139.373 102.691,139.373 103.181,138.883 v1(103.323,138.883)
Y6: P1.18 U1.N4 | length 22.3
  Top Layer w0.254: P1.18@90.08,130.694 v1(91.11,130.694) ; v1(104.191,138.989) U1.N4@104.528,139.326
  Bottom Layer w0.1: v1(91.11,130.694) 91.66,130.694 91.73,130.764 91.73,130.865 91.801,130.935 92.06,130.935 92.13,130.865 92.13,130.764 92.201,130.694 92.46,130.694 92.53,130.764 92.53,130.894 92.601,130.964 92.86,130.964 92.93,130.894 92.93,130.764 93.001,130.694 93.26,130.694 93.33,130.764 93.33,130.894 93.401,130.964 93.66,130.964 93.73,130.894 93.73,130.764 93.801,130.694 93.991,130.694 94.239,130.942 94.239,131.042 94.057,131.224 94.057,131.324 94.239,131.507 94.339,131.507 94.522,131.325 94.622,131.325 94.805,131.508 94.805,131.608 94.622,131.79 94.622,131.89 94.805,132.073 94.905,132.073 95.087,131.89 95.187,131.89 95.37,132.073 95.37,132.173 95.188,132.356 95.188,132.456 95.371,132.639 95.471,132.639 95.653,132.456 95.753,132.456 95.936,132.639 95.936,132.739 95.754,132.921 95.754,133.021 95.936,133.204 96.036,133.204 96.219,133.022 96.319,133.022 96.502,133.205 96.502,133.305 96.319,133.487 96.319,133.587 96.502,133.77 96.602,133.77 96.785,133.588 96.885,133.588 99.823,136.526 101.587,136.526 104.05,138.989 v1(104.191,138.989)
Y7: P1.16 U1.N5 | length 23
  Top Layer w0.254: P1.16@90.081,129.694 v1(91.11,129.694) ; v1(104.953,138.989) 104.991,138.989 U1.N5@105.328,139.326
  Bottom Layer w0.1: v1(91.11,129.694) 91.611,129.694 91.682,129.764 91.682,129.817 91.753,129.887 92.011,129.887 92.082,129.817 92.082,129.764 92.153,129.694 92.411,129.694 92.482,129.764 92.482,129.894 92.553,129.965 92.811,129.965 92.882,129.894 92.882,129.764 92.953,129.694 93.211,129.694 93.282,129.764 93.282,129.894 93.353,129.965 93.611,129.965 93.682,129.894 93.682,129.764 93.753,129.694 94.011,129.694 94.082,129.764 94.082,129.894 94.153,129.965 94.411,129.965 94.482,129.894 94.482,129.764 94.553,129.694 95.08,129.694 95.249,129.863 95.249,129.963 95.003,130.209 95.003,130.309 95.185,130.491 95.285,130.491 95.531,130.246 95.631,130.246 95.814,130.428 95.814,130.528 95.568,130.774 95.568,130.874 95.751,131.057 95.851,131.057 96.097,130.811 96.197,130.811 96.38,130.994 96.38,131.094 96.134,131.34 96.134,131.44 96.317,131.623 96.417,131.623 96.663,131.377 96.763,131.377 103.973,138.587 104.358,138.587 104.76,138.989 v1(104.953,138.989)
Y8: P1.14 U1.P4 | length 23
  Top Layer w0.254: P1.14@90.08,128.695 v1(91.491,128.695) ; v1(104.08,138.126) 104.128,138.126 U1.P4@104.528,138.526
  Bottom Layer w0.1: v1(91.491,128.695) 91.831,128.695 91.901,128.765 91.901,129.394 91.972,129.464 92.231,129.464 92.301,129.394 92.301,128.765 92.372,128.695 92.631,128.695 92.701,128.765 92.701,129.394 92.772,129.464 93.031,129.464 93.101,129.394 93.101,128.765 93.172,128.695 93.431,128.695 93.501,128.765 93.501,129.394 93.572,129.464 93.831,129.464 93.901,129.394 93.901,128.765 93.972,128.695 94.649,128.695 94.885,128.931 95.027,128.931 95.239,129.143 95.239,129.285 95.451,129.497 95.593,129.497 95.805,129.709 95.805,129.85 96.017,130.062 96.158,130.062 96.37,130.275 96.37,130.416 96.582,130.628 96.724,130.628 96.936,130.84 96.936,130.982 v1(104.08,138.126)
Y9: P1.12 U1.P5 | length 23.1
  Top Layer w0.254: P1.12@90.08,127.695 91.482,127.695 v1(91.491,127.686) ; v1@104.93,138.077 104.93,138.128 U1.P5@105.328,138.526
  Bottom Layer w0.1: v1(91.491,127.686) 91.772,127.686 91.843,127.615 91.843,127.122 91.913,127.051 92.172,127.051 92.243,127.122 92.243,127.615 92.313,127.686 92.572,127.686 92.643,127.615 92.643,127.122 92.713,127.051 92.972,127.051 93.043,127.122 93.043,127.615 93.113,127.686 93.372,127.686 93.443,127.615 93.443,127.122 93.513,127.051 93.772,127.051 93.843,127.122 93.843,127.615 93.913,127.686 94.535,127.686 v1(104.928,138.079)
pads on no net: P1.1 P1.23 P1.24 SCREW1.1 SCREW2.1 SCREW3.1 SCREW4.1 U1.A10 U1.A11 U1.A12 U1.A13 U1.A14 U1.A15 U1.B3 U1.B7 U1.B8 U1.B9 U1.B10 U1.B11 U1.B12 U1.B13 U1.B14 U1.B15 U1.B16 U1.C1 U1.C2 U1.C3 U1.C4 U1.C5 U1.C6 U1.C9 U1.C10 U1.C11 U1.C12 U1.C13 U1.C14 U1.C15 U1.C16 U1.D1 U1.D3 U1.D4 U1.D5 U1.D6 U1.D7 U1.D8 U1.D9 U1.D10 U1.D11 U1.D12 U1.D13 U1.E3 U1.E4 U1.E5 U1.E6 U1.E7 U1.E8 U1.E9 U1.E10 U1.E11 U1.E12 U1.E13 U1.E14 U1.F3 U1.F4 U1.F5 U1.F12 U1.F13 U1.F14 U1.G3 U1.G4 U1.G5 U1.G12 U1.G13 U1.G14 U1.H2 U1.H3 U1.H4 U1.H5 U1.H12 U1.H13 U1.H14 U1.J3 U1.J4 U1.J5 U1.J12 U1.J13 U1.K3 U1.K4 U1.K5 U1.K13 U1.K14 U1.K15 U1.L2 U1.L3 U1.L4 U1.L5 U1.L13 U1.L14 U1.L16 U1.M1 U1.M2 U1.M3 U1.M4 U1.M5 U1.M6 U1.M7 U1.M9 U1.M11 U1.M12 U1.M13 U1.N8 U1.N9 U1.N11 U1.N12 U1.N14 U1.N16 U1.P3 U1.P7 U1.P8 U1.P11 U1.P12 U1.P13 U1.P14 U1.P15 U1.R2 U1.R3 U1.R4 U1.R5 U1.R6 U1.R7 U1.R8 U1.R12 U1.R14 U1.T13 U2.4 U2.15 U2.16 U2.26 U2.28 U2.29 U2.30 U2.32 U2.33 U2.34 U2.35 U2.38 U2.39 U5.40 U8.4 USB1.A8 USB1.B6 USB1.B7 USB1.B8
copper on no net: | length 23.8
  Top Layer w0.1: 93.396,116.51 93.645,116.261 93.645,114.973 ; 94.285,116.129 94.915,115.499 94.915,114.973 ; 96.185,97.473 96.414,97.244 v1(96.414,95.839) ; 105.075,114.973 105.075,115.608 106.612,117.145 107.239,117.145 107.493,116.891 ; v1@109.779,138.227 109.829,138.227 110.128,138.526 ; 110.165,99.238 111.176,99.238 111.684,98.73 ; 111.728,148.926 111.938,149.136 v1(111.938,149.276) ; 112.528,148.926 112.827,149.225 v1(112.827,149.276) ; 113.328,148.126 v1(113.716,148.514) ; 113.328,148.926 113.678,149.276 v1(113.716,149.276) ; 114.128,148.126 114.516,148.514 v1@114.605,148.514
  Bottom Layer w0.1: v1(96.414,95.839) 96.571,95.682 96.571,93.904 ; v1(109.78,138.226) 110.16,137.846 110.16,137.719 ; v1(111.938,149.276) 112.319,149.657 112.319,150.165 112.39,150.236 113.025,150.236 113.335,150.546 ; v1(112.827,149.276) 112.827,149.657 ; v1(113.716,148.514) 114.203,149.001 114.203,149.57 114.351,149.718 114.351,150.673 ; v1(113.716,149.276) 113.716,149.784 ; v1(114.546,148.573) 115.113,149.139 115.113,150.546
  other v2: 76.505,155.418 76.505,156.218 76.505,157.018 76.505,157.818 76.505,158.618 76.505,159.418 76.505,160.218 76.505,161.018 76.505,161.818 76.505,162.618 76.505,163.418 76.505,164.218 76.505,165.018 76.505,165.818 76.505,166.618 76.505,167.518

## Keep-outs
Board Outline Layer:
  lines w0.254: 84.506,76.2 148.506,76.2 148.506,170.866 84.506,170.866 84.506,76.2

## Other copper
Top Layer:
  region net TCK: 120.193,166.929 120.701,166.929 120.701,166.528 120.188,166.528 120.193,166.533
  region net TDO: 121.298,166.887 121.806,166.887 121.806,166.486 121.292,166.486 121.298,166.491
  region net TDI: 126.545,166.976 127.053,166.976 127.053,166.575 126.54,166.575 126.545,166.58
  region net TMS: 127.667,166.672 128.175,166.672 128.175,166.27 127.662,166.27 127.667,166.276
  region net +3V3: 130.356,166.749 130.864,166.749 130.864,166.347 130.35,166.347 130.356,166.353
  region net GND: 132.896,166.749 133.404,166.749 133.404,166.347 132.89,166.347 132.896,166.353
  region net GND: 92.124,117.033 92.632,117.033 92.632,116.632 92.118,116.632 92.124,116.637
  region net GND: 89.93,119.942 89.93,120.45 90.331,120.45 90.331,119.936 90.326,119.942
  region net +3V3: 91.113,123.823 91.621,123.823 91.621,123.421 91.107,123.421 91.113,123.427
  region net DN: 92.002,86.485 92.51,86.485 92.51,86.083 91.996,86.083 92.002,86.089
  region net DP: 91.367,86.993 91.875,86.993 91.875,86.591 91.361,86.591 91.367,86.597
  region net GND: 94.034,86.485 94.542,86.485 94.542,86.083 94.028,86.083 94.034,86.089
  region net GND: 96.066,82.04 96.574,82.04 96.574,81.638 96.06,81.638 96.066,81.644
  region net +5V: 96.047,82.948 96.555,82.948 96.555,82.546 96.041,82.546 96.047,82.552
  region net +1V8: 123.194,95.465 123.702,95.465 123.702,95.063 123.189,95.063 123.194,95.068
  region net GND: 121.713,93.434 122.221,93.434 122.221,93.033 121.708,93.033 121.713,93.038
  region net GND: 141.83,91.594 142.338,91.594 142.338,91.193 141.825,91.193 141.83,91.198
  region net +3V3: 94.003,146.831 94.511,146.831 94.511,146.43 93.998,146.43 94.003,146.435
  region net GND: 112.957,157.351 113.465,157.351 113.465,156.949 112.951,156.949 112.957,156.955
  region net +1V1: 140.43,91.633 140.938,91.633 140.938,91.232 140.425,91.232 140.43,91.237
  region: 93.145,116.711 93.653,116.711 93.653,116.309 93.139,116.309 93.145,116.315
  region: 94.034,116.33 94.542,116.33 94.542,115.928 94.028,115.928 94.034,115.934
Bottom Layer:
  region net DONE: 110.614,127.181 111.122,127.181 111.122,126.78 110.609,126.78 110.614,126.785
  region net +1V1: 111.56,127.608 112.068,127.608 112.068,127.207 111.554,127.207 111.56,127.212
  region net PROGRAMN: 108.639,126.214 109.147,126.214 109.147,125.813 108.633,125.813 108.639,125.818
  region net RESET: 99.498,121.275 100.006,121.275 100.006,120.873 99.492,120.873 99.498,120.879
  region net +1V8: 92.043,120.12 92.551,120.12 92.551,119.719 92.038,119.719 92.043,119.724
  region net INITN: 93.422,117.577 93.93,117.577 93.93,117.175 93.416,117.175 93.422,117.181
  region net GND: 91.875,119.251 92.383,119.251 92.383,118.849 91.869,118.849 91.875,118.855
  region net GND: 109.782,126.236 110.29,126.236 110.29,125.834 109.776,125.834 109.782,125.84
  region: 109.842,137.894 110.282,138.148 110.483,137.801 110.038,137.544 110.04,137.551
  region: 113.465,149.985 113.973,149.985 113.973,149.583 113.459,149.583 113.465,149.589
  region: 112.576,149.985 113.084,149.985 113.084,149.583 112.57,149.583 112.576,149.589
  region: 113.084,150.747 113.592,150.747 113.592,150.345 113.078,150.345 113.084,150.351
  region: 114.862,150.747 115.37,150.747 115.37,150.345 114.856,150.345 114.862,150.351
  region: 114.1,150.874 114.608,150.874 114.608,150.472 114.094,150.472 114.1,150.478

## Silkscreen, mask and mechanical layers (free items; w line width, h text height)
Top Silkscreen Layer:
  text "JTAG" at 134.417,166.802 h3.05 r180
